VERSION 5.7 ;
  NOWIREEXTENSIONATPIN ON ;
  DIVIDERCHAR "/" ;
  BUSBITCHARS "[]" ;
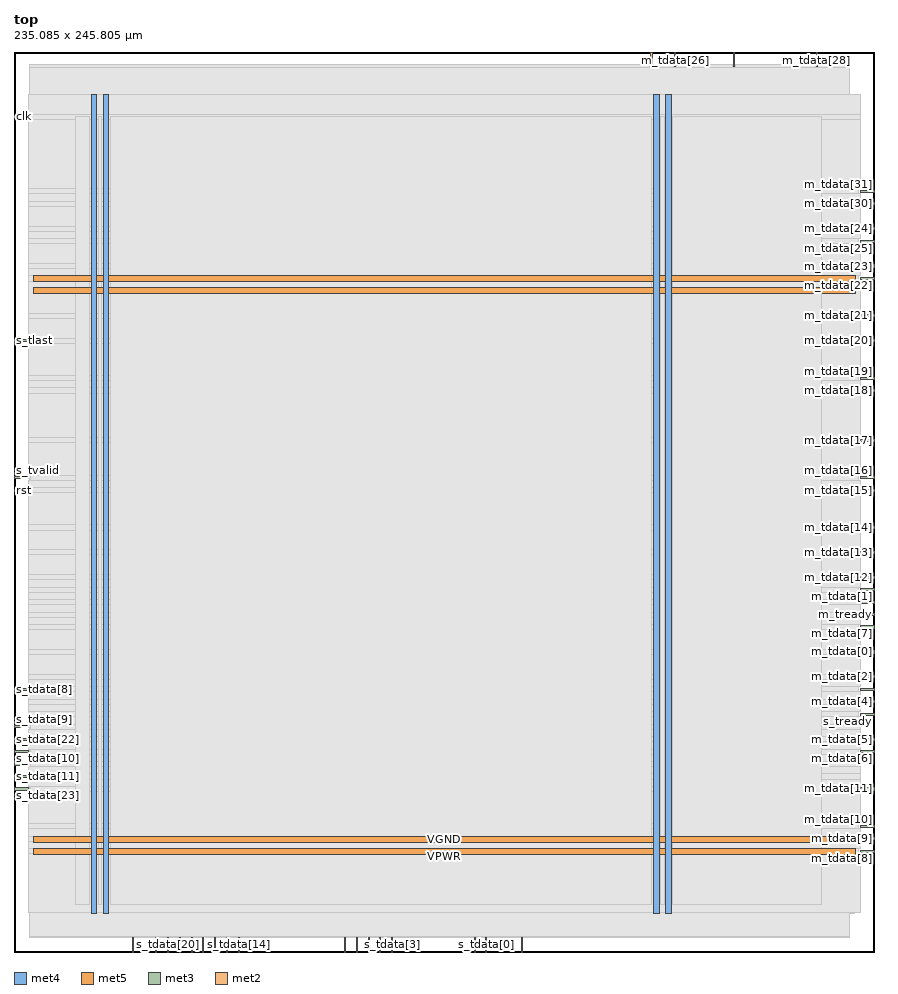
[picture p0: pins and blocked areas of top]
MACRO top
  CLASS BLOCK ;
  FOREIGN top ;
  ORIGIN 0.000 0.000 ;
  SIZE 235.085 BY 245.805 ;
  PIN VGND
    DIRECTION INOUT ;
    USE GROUND ;
    PORT
      LAYER met4 ;
        RECT 24.340 10.640 25.940 234.160 ;
    END
    PORT
      LAYER met4 ;
        RECT 177.940 10.640 179.540 234.160 ;
    END
    PORT
      LAYER met5 ;
        RECT 5.280 30.030 229.780 31.630 ;
    END
    PORT
      LAYER met5 ;
        RECT 5.280 183.210 229.780 184.810 ;
    END
  END VGND
  PIN VPWR
    DIRECTION INOUT ;
    USE POWER ;
    PORT
      LAYER met4 ;
        RECT 21.040 10.640 22.640 234.160 ;
    END
    PORT
      LAYER met4 ;
        RECT 174.640 10.640 176.240 234.160 ;
    END
    PORT
      LAYER met5 ;
        RECT 5.280 26.730 229.780 28.330 ;
    END
    PORT
      LAYER met5 ;
        RECT 5.280 179.910 229.780 181.510 ;
    END
  END VPWR
  PIN clk
    DIRECTION INPUT ;
    USE SIGNAL ;
    ANTENNAGATEAREA 0.852000 ;
    PORT
      LAYER met3 ;
        RECT 0.000 227.840 4.000 228.440 ;
    END
  END clk
  PIN m_tdata[0]
    DIRECTION OUTPUT ;
    USE SIGNAL ;
    ANTENNADIFFAREA 0.445500 ;
    PORT
      LAYER met3 ;
        RECT 231.085 81.640 235.085 82.240 ;
    END
  END m_tdata[0]
  PIN m_tdata[10]
    DIRECTION OUTPUT ;
    USE SIGNAL ;
    ANTENNADIFFAREA 0.445500 ;
    PORT
      LAYER met3 ;
        RECT 231.085 34.040 235.085 34.640 ;
    END
  END m_tdata[10]
  PIN m_tdata[11]
    DIRECTION OUTPUT ;
    USE SIGNAL ;
    ANTENNADIFFAREA 0.445500 ;
    PORT
      LAYER met3 ;
        RECT 231.085 44.240 235.085 44.840 ;
    END
  END m_tdata[11]
  PIN m_tdata[12]
    DIRECTION OUTPUT ;
    USE SIGNAL ;
    ANTENNADIFFAREA 0.445500 ;
    PORT
      LAYER met3 ;
        RECT 231.085 102.040 235.085 102.640 ;
    END
  END m_tdata[12]
  PIN m_tdata[13]
    DIRECTION OUTPUT ;
    USE SIGNAL ;
    ANTENNADIFFAREA 0.445500 ;
    PORT
      LAYER met3 ;
        RECT 231.085 108.840 235.085 109.440 ;
    END
  END m_tdata[13]
  PIN m_tdata[14]
    DIRECTION OUTPUT ;
    USE SIGNAL ;
    ANTENNADIFFAREA 0.445500 ;
    PORT
      LAYER met3 ;
        RECT 231.085 115.640 235.085 116.240 ;
    END
  END m_tdata[14]
  PIN m_tdata[15]
    DIRECTION OUTPUT ;
    USE SIGNAL ;
    ANTENNADIFFAREA 0.445500 ;
    PORT
      LAYER met3 ;
        RECT 231.085 125.840 235.085 126.440 ;
    END
  END m_tdata[15]
  PIN m_tdata[16]
    DIRECTION OUTPUT ;
    USE SIGNAL ;
    ANTENNADIFFAREA 0.445500 ;
    PORT
      LAYER met3 ;
        RECT 231.085 129.240 235.085 129.840 ;
    END
  END m_tdata[16]
  PIN m_tdata[17]
    DIRECTION OUTPUT ;
    USE SIGNAL ;
    ANTENNADIFFAREA 0.445500 ;
    PORT
      LAYER met3 ;
        RECT 231.085 139.440 235.085 140.040 ;
    END
  END m_tdata[17]
  PIN m_tdata[18]
    DIRECTION OUTPUT ;
    USE SIGNAL ;
    ANTENNADIFFAREA 0.445500 ;
    PORT
      LAYER met3 ;
        RECT 231.085 153.040 235.085 153.640 ;
    END
  END m_tdata[18]
  PIN m_tdata[19]
    DIRECTION OUTPUT ;
    USE SIGNAL ;
    ANTENNADIFFAREA 0.445500 ;
    PORT
      LAYER met3 ;
        RECT 231.085 156.440 235.085 157.040 ;
    END
  END m_tdata[19]
  PIN m_tdata[1]
    DIRECTION OUTPUT ;
    USE SIGNAL ;
    ANTENNADIFFAREA 0.445500 ;
    PORT
      LAYER met3 ;
        RECT 231.085 98.640 235.085 99.240 ;
    END
  END m_tdata[1]
  PIN m_tdata[20]
    DIRECTION OUTPUT ;
    USE SIGNAL ;
    ANTENNADIFFAREA 0.445500 ;
    PORT
      LAYER met3 ;
        RECT 231.085 166.640 235.085 167.240 ;
    END
  END m_tdata[20]
  PIN m_tdata[21]
    DIRECTION OUTPUT ;
    USE SIGNAL ;
    ANTENNADIFFAREA 0.445500 ;
    PORT
      LAYER met3 ;
        RECT 231.085 173.440 235.085 174.040 ;
    END
  END m_tdata[21]
  PIN m_tdata[22]
    DIRECTION OUTPUT ;
    USE SIGNAL ;
    ANTENNADIFFAREA 0.445500 ;
    PORT
      LAYER met3 ;
        RECT 231.085 183.640 235.085 184.240 ;
    END
  END m_tdata[22]
  PIN m_tdata[23]
    DIRECTION OUTPUT ;
    USE SIGNAL ;
    ANTENNADIFFAREA 0.445500 ;
    PORT
      LAYER met3 ;
        RECT 231.085 187.040 235.085 187.640 ;
    END
  END m_tdata[23]
  PIN m_tdata[24]
    DIRECTION OUTPUT ;
    USE SIGNAL ;
    ANTENNADIFFAREA 0.445500 ;
    PORT
      LAYER met3 ;
        RECT 231.085 197.240 235.085 197.840 ;
    END
  END m_tdata[24]
  PIN m_tdata[25]
    DIRECTION OUTPUT ;
    USE SIGNAL ;
    ANTENNADIFFAREA 0.445500 ;
    PORT
      LAYER met3 ;
        RECT 231.085 193.840 235.085 194.440 ;
    END
  END m_tdata[25]
  PIN m_tdata[26]
    DIRECTION OUTPUT ;
    USE SIGNAL ;
    ANTENNADIFFAREA 0.795200 ;
    PORT
      LAYER met2 ;
        RECT 180.410 241.805 180.690 245.805 ;
    END
  END m_tdata[26]
  PIN m_tdata[27]
    DIRECTION OUTPUT ;
    USE SIGNAL ;
    ANTENNADIFFAREA 0.795200 ;
    PORT
      LAYER met2 ;
        RECT 173.970 241.805 174.250 245.805 ;
    END
  END m_tdata[27]
  PIN m_tdata[28]
    DIRECTION OUTPUT ;
    USE SIGNAL ;
    ANTENNADIFFAREA 0.795200 ;
    PORT
      LAYER met2 ;
        RECT 219.050 241.805 219.330 245.805 ;
    END
  END m_tdata[28]
  PIN m_tdata[29]
    DIRECTION OUTPUT ;
    USE SIGNAL ;
    ANTENNADIFFAREA 0.795200 ;
    PORT
      LAYER met2 ;
        RECT 196.510 241.805 196.790 245.805 ;
    END
  END m_tdata[29]
  PIN m_tdata[2]
    DIRECTION OUTPUT ;
    USE SIGNAL ;
    ANTENNADIFFAREA 0.445500 ;
    PORT
      LAYER met3 ;
        RECT 231.085 74.840 235.085 75.440 ;
    END
  END m_tdata[2]
  PIN m_tdata[30]
    DIRECTION OUTPUT ;
    USE SIGNAL ;
    ANTENNADIFFAREA 0.445500 ;
    PORT
      LAYER met3 ;
        RECT 231.085 204.040 235.085 204.640 ;
    END
  END m_tdata[30]
  PIN m_tdata[31]
    DIRECTION OUTPUT ;
    USE SIGNAL ;
    ANTENNADIFFAREA 0.445500 ;
    PORT
      LAYER met3 ;
        RECT 231.085 207.440 235.085 208.040 ;
    END
  END m_tdata[31]
  PIN m_tdata[3]
    DIRECTION OUTPUT ;
    USE SIGNAL ;
    ANTENNADIFFAREA 0.445500 ;
    PORT
      LAYER met3 ;
        RECT 231.085 71.440 235.085 72.040 ;
    END
  END m_tdata[3]
  PIN m_tdata[4]
    DIRECTION OUTPUT ;
    USE SIGNAL ;
    ANTENNADIFFAREA 0.445500 ;
    PORT
      LAYER met3 ;
        RECT 231.085 68.040 235.085 68.640 ;
    END
  END m_tdata[4]
  PIN m_tdata[5]
    DIRECTION OUTPUT ;
    USE SIGNAL ;
    ANTENNADIFFAREA 0.445500 ;
    PORT
      LAYER met3 ;
        RECT 231.085 57.840 235.085 58.440 ;
    END
  END m_tdata[5]
  PIN m_tdata[6]
    DIRECTION OUTPUT ;
    USE SIGNAL ;
    ANTENNADIFFAREA 0.445500 ;
    PORT
      LAYER met3 ;
        RECT 231.085 54.440 235.085 55.040 ;
    END
  END m_tdata[6]
  PIN m_tdata[7]
    DIRECTION OUTPUT ;
    USE SIGNAL ;
    ANTENNADIFFAREA 0.445500 ;
    PORT
      LAYER met3 ;
        RECT 231.085 88.440 235.085 89.040 ;
    END
  END m_tdata[7]
  PIN m_tdata[8]
    DIRECTION OUTPUT ;
    USE SIGNAL ;
    ANTENNADIFFAREA 0.445500 ;
    PORT
      LAYER met3 ;
        RECT 231.085 27.240 235.085 27.840 ;
    END
  END m_tdata[8]
  PIN m_tdata[9]
    DIRECTION OUTPUT ;
    USE SIGNAL ;
    ANTENNADIFFAREA 0.445500 ;
    PORT
      LAYER met3 ;
        RECT 231.085 30.640 235.085 31.240 ;
    END
  END m_tdata[9]
  PIN m_tready
    DIRECTION INPUT ;
    USE SIGNAL ;
    ANTENNAGATEAREA 0.196500 ;
    PORT
      LAYER met3 ;
        RECT 231.085 91.840 235.085 92.440 ;
    END
  END m_tready
  PIN m_tvalid
    DIRECTION OUTPUT ;
    USE SIGNAL ;
    ANTENNADIFFAREA 0.445500 ;
    PORT
      LAYER met3 ;
        RECT 231.085 95.240 235.085 95.840 ;
    END
  END m_tvalid
  PIN rst
    DIRECTION INPUT ;
    USE SIGNAL ;
    ANTENNAGATEAREA 0.213000 ;
    PORT
      LAYER met3 ;
        RECT 0.000 125.840 4.000 126.440 ;
    END
  END rst
  PIN s_tdata[0]
    DIRECTION INPUT ;
    USE SIGNAL ;
    ANTENNAGATEAREA 0.196500 ;
    PORT
      LAYER met2 ;
        RECT 128.890 0.000 129.170 4.000 ;
    END
  END s_tdata[0]
  PIN s_tdata[10]
    DIRECTION INPUT ;
    USE SIGNAL ;
    ANTENNAGATEAREA 0.196500 ;
    PORT
      LAYER met3 ;
        RECT 0.000 54.440 4.000 55.040 ;
    END
  END s_tdata[10]
  PIN s_tdata[11]
    DIRECTION INPUT ;
    USE SIGNAL ;
    ANTENNAGATEAREA 0.126000 ;
    PORT
      LAYER met3 ;
        RECT 0.000 47.640 4.000 48.240 ;
    END
  END s_tdata[11]
  PIN s_tdata[12]
    DIRECTION INPUT ;
    USE SIGNAL ;
    ANTENNAGATEAREA 0.126000 ;
    PORT
      LAYER met2 ;
        RECT 38.730 0.000 39.010 4.000 ;
    END
  END s_tdata[12]
  PIN s_tdata[13]
    DIRECTION INPUT ;
    USE SIGNAL ;
    ANTENNAGATEAREA 0.213000 ;
    PORT
      LAYER met2 ;
        RECT 32.290 0.000 32.570 4.000 ;
    END
  END s_tdata[13]
  PIN s_tdata[14]
    DIRECTION INPUT ;
    USE SIGNAL ;
    ANTENNAGATEAREA 0.196500 ;
    PORT
      LAYER met2 ;
        RECT 61.270 0.000 61.550 4.000 ;
    END
  END s_tdata[14]
  PIN s_tdata[15]
    DIRECTION INPUT ;
    USE SIGNAL ;
    ANTENNAGATEAREA 0.196500 ;
    PORT
      LAYER met2 ;
        RECT 51.610 0.000 51.890 4.000 ;
    END
  END s_tdata[15]
  PIN s_tdata[16]
    DIRECTION INPUT ;
    USE SIGNAL ;
    ANTENNAGATEAREA 0.126000 ;
    PORT
      LAYER met2 ;
        RECT 58.050 0.000 58.330 4.000 ;
    END
  END s_tdata[16]
  PIN s_tdata[17]
    DIRECTION INPUT ;
    USE SIGNAL ;
    ANTENNAGATEAREA 0.196500 ;
    PORT
      LAYER met2 ;
        RECT 54.830 0.000 55.110 4.000 ;
    END
  END s_tdata[17]
  PIN s_tdata[18]
    DIRECTION INPUT ;
    USE SIGNAL ;
    ANTENNAGATEAREA 0.196500 ;
    PORT
      LAYER met2 ;
        RECT 48.390 0.000 48.670 4.000 ;
    END
  END s_tdata[18]
  PIN s_tdata[19]
    DIRECTION INPUT ;
    USE SIGNAL ;
    ANTENNAGATEAREA 0.126000 ;
    PORT
      LAYER met2 ;
        RECT 45.170 0.000 45.450 4.000 ;
    END
  END s_tdata[19]
  PIN s_tdata[1]
    DIRECTION INPUT ;
    USE SIGNAL ;
    ANTENNAGATEAREA 0.196500 ;
    PORT
      LAYER met2 ;
        RECT 138.550 0.000 138.830 4.000 ;
    END
  END s_tdata[1]
  PIN s_tdata[20]
    DIRECTION INPUT ;
    USE SIGNAL ;
    ANTENNAGATEAREA 0.196500 ;
    PORT
      LAYER met2 ;
        RECT 41.950 0.000 42.230 4.000 ;
    END
  END s_tdata[20]
  PIN s_tdata[21]
    DIRECTION INPUT ;
    USE SIGNAL ;
    ANTENNAGATEAREA 0.196500 ;
    PORT
      LAYER met3 ;
        RECT 0.000 51.040 4.000 51.640 ;
    END
  END s_tdata[21]
  PIN s_tdata[22]
    DIRECTION INPUT ;
    USE SIGNAL ;
    ANTENNAGATEAREA 0.213000 ;
    PORT
      LAYER met3 ;
        RECT 0.000 57.840 4.000 58.440 ;
    END
  END s_tdata[22]
  PIN s_tdata[23]
    DIRECTION INPUT ;
    USE SIGNAL ;
    ANTENNAGATEAREA 0.196500 ;
    PORT
      LAYER met3 ;
        RECT 0.000 44.240 4.000 44.840 ;
    END
  END s_tdata[23]
  PIN s_tdata[2]
    DIRECTION INPUT ;
    USE SIGNAL ;
    ANTENNAGATEAREA 0.196500 ;
    PORT
      LAYER met2 ;
        RECT 125.670 0.000 125.950 4.000 ;
    END
  END s_tdata[2]
  PIN s_tdata[3]
    DIRECTION INPUT ;
    USE SIGNAL ;
    ANTENNAGATEAREA 0.196500 ;
    PORT
      LAYER met2 ;
        RECT 103.130 0.000 103.410 4.000 ;
    END
  END s_tdata[3]
  PIN s_tdata[4]
    DIRECTION INPUT ;
    USE SIGNAL ;
    ANTENNAGATEAREA 0.196500 ;
    PORT
      LAYER met2 ;
        RECT 90.250 0.000 90.530 4.000 ;
    END
  END s_tdata[4]
  PIN s_tdata[5]
    DIRECTION INPUT ;
    USE SIGNAL ;
    ANTENNAGATEAREA 0.196500 ;
    PORT
      LAYER met2 ;
        RECT 93.470 0.000 93.750 4.000 ;
    END
  END s_tdata[5]
  PIN s_tdata[6]
    DIRECTION INPUT ;
    USE SIGNAL ;
    ANTENNAGATEAREA 0.196500 ;
    PORT
      LAYER met2 ;
        RECT 99.910 0.000 100.190 4.000 ;
    END
  END s_tdata[6]
  PIN s_tdata[7]
    DIRECTION INPUT ;
    USE SIGNAL ;
    ANTENNAGATEAREA 0.196500 ;
    PORT
      LAYER met2 ;
        RECT 96.690 0.000 96.970 4.000 ;
    END
  END s_tdata[7]
  PIN s_tdata[8]
    DIRECTION INPUT ;
    USE SIGNAL ;
    ANTENNAGATEAREA 0.159000 ;
    PORT
      LAYER met3 ;
        RECT 0.000 71.440 4.000 72.040 ;
    END
  END s_tdata[8]
  PIN s_tdata[9]
    DIRECTION INPUT ;
    USE SIGNAL ;
    ANTENNAGATEAREA 0.196500 ;
    PORT
      LAYER met3 ;
        RECT 0.000 61.240 4.000 61.840 ;
    END
  END s_tdata[9]
  PIN s_tlast
    DIRECTION INPUT ;
    USE SIGNAL ;
    ANTENNAGATEAREA 0.196500 ;
    PORT
      LAYER met3 ;
        RECT 0.000 166.640 4.000 167.240 ;
    END
  END s_tlast
  PIN s_tready
    DIRECTION OUTPUT ;
    USE SIGNAL ;
    ANTENNADIFFAREA 0.445500 ;
    PORT
      LAYER met3 ;
        RECT 231.085 64.640 235.085 65.240 ;
    END
  END s_tready
  PIN s_tvalid
    DIRECTION INPUT ;
    USE SIGNAL ;
    ANTENNAGATEAREA 0.196500 ;
    PORT
      LAYER met3 ;
        RECT 0.000 129.240 4.000 129.840 ;
    END
  END s_tvalid
  OBS
      LAYER nwell ;
        RECT 5.330 10.795 229.730 234.005 ;
      LAYER li1 ;
        RECT 5.520 10.795 229.540 234.005 ;
      LAYER met1 ;
        RECT 4.210 10.640 229.540 234.160 ;
      LAYER met2 ;
        RECT 4.230 241.525 173.690 242.490 ;
        RECT 174.530 241.525 180.130 242.490 ;
        RECT 180.970 241.525 196.230 242.490 ;
        RECT 197.070 241.525 218.770 242.490 ;
        RECT 219.610 241.525 228.070 242.490 ;
        RECT 4.230 4.280 228.070 241.525 ;
        RECT 4.230 4.000 32.010 4.280 ;
        RECT 32.850 4.000 38.450 4.280 ;
        RECT 39.290 4.000 41.670 4.280 ;
        RECT 42.510 4.000 44.890 4.280 ;
        RECT 45.730 4.000 48.110 4.280 ;
        RECT 48.950 4.000 51.330 4.280 ;
        RECT 52.170 4.000 54.550 4.280 ;
        RECT 55.390 4.000 57.770 4.280 ;
        RECT 58.610 4.000 60.990 4.280 ;
        RECT 61.830 4.000 89.970 4.280 ;
        RECT 90.810 4.000 93.190 4.280 ;
        RECT 94.030 4.000 96.410 4.280 ;
        RECT 97.250 4.000 99.630 4.280 ;
        RECT 100.470 4.000 102.850 4.280 ;
        RECT 103.690 4.000 125.390 4.280 ;
        RECT 126.230 4.000 128.610 4.280 ;
        RECT 129.450 4.000 138.270 4.280 ;
        RECT 139.110 4.000 228.070 4.280 ;
      LAYER met3 ;
        RECT 3.990 228.840 231.085 234.085 ;
        RECT 4.400 227.440 231.085 228.840 ;
        RECT 3.990 208.440 231.085 227.440 ;
        RECT 3.990 207.040 230.685 208.440 ;
        RECT 3.990 205.040 231.085 207.040 ;
        RECT 3.990 203.640 230.685 205.040 ;
        RECT 3.990 198.240 231.085 203.640 ;
        RECT 3.990 196.840 230.685 198.240 ;
        RECT 3.990 194.840 231.085 196.840 ;
        RECT 3.990 193.440 230.685 194.840 ;
        RECT 3.990 188.040 231.085 193.440 ;
        RECT 3.990 186.640 230.685 188.040 ;
        RECT 3.990 184.640 231.085 186.640 ;
        RECT 3.990 183.240 230.685 184.640 ;
        RECT 3.990 174.440 231.085 183.240 ;
        RECT 3.990 173.040 230.685 174.440 ;
        RECT 3.990 167.640 231.085 173.040 ;
        RECT 4.400 166.240 230.685 167.640 ;
        RECT 3.990 157.440 231.085 166.240 ;
        RECT 3.990 156.040 230.685 157.440 ;
        RECT 3.990 154.040 231.085 156.040 ;
        RECT 3.990 152.640 230.685 154.040 ;
        RECT 3.990 140.440 231.085 152.640 ;
        RECT 3.990 139.040 230.685 140.440 ;
        RECT 3.990 130.240 231.085 139.040 ;
        RECT 4.400 128.840 230.685 130.240 ;
        RECT 3.990 126.840 231.085 128.840 ;
        RECT 4.400 125.440 230.685 126.840 ;
        RECT 3.990 116.640 231.085 125.440 ;
        RECT 3.990 115.240 230.685 116.640 ;
        RECT 3.990 109.840 231.085 115.240 ;
        RECT 3.990 108.440 230.685 109.840 ;
        RECT 3.990 103.040 231.085 108.440 ;
        RECT 3.990 101.640 230.685 103.040 ;
        RECT 3.990 99.640 231.085 101.640 ;
        RECT 3.990 98.240 230.685 99.640 ;
        RECT 3.990 96.240 231.085 98.240 ;
        RECT 3.990 94.840 230.685 96.240 ;
        RECT 3.990 92.840 231.085 94.840 ;
        RECT 3.990 91.440 230.685 92.840 ;
        RECT 3.990 89.440 231.085 91.440 ;
        RECT 3.990 88.040 230.685 89.440 ;
        RECT 3.990 82.640 231.085 88.040 ;
        RECT 3.990 81.240 230.685 82.640 ;
        RECT 3.990 75.840 231.085 81.240 ;
        RECT 3.990 74.440 230.685 75.840 ;
        RECT 3.990 72.440 231.085 74.440 ;
        RECT 4.400 71.040 230.685 72.440 ;
        RECT 3.990 69.040 231.085 71.040 ;
        RECT 3.990 67.640 230.685 69.040 ;
        RECT 3.990 65.640 231.085 67.640 ;
        RECT 3.990 64.240 230.685 65.640 ;
        RECT 3.990 62.240 231.085 64.240 ;
        RECT 4.400 60.840 231.085 62.240 ;
        RECT 3.990 58.840 231.085 60.840 ;
        RECT 4.400 57.440 230.685 58.840 ;
        RECT 3.990 55.440 231.085 57.440 ;
        RECT 4.400 54.040 230.685 55.440 ;
        RECT 3.990 52.040 231.085 54.040 ;
        RECT 4.400 50.640 231.085 52.040 ;
        RECT 3.990 48.640 231.085 50.640 ;
        RECT 4.400 47.240 231.085 48.640 ;
        RECT 3.990 45.240 231.085 47.240 ;
        RECT 4.400 43.840 230.685 45.240 ;
        RECT 3.990 35.040 231.085 43.840 ;
        RECT 3.990 33.640 230.685 35.040 ;
        RECT 3.990 31.640 231.085 33.640 ;
        RECT 3.990 30.240 230.685 31.640 ;
        RECT 3.990 28.240 231.085 30.240 ;
        RECT 3.990 26.840 230.685 28.240 ;
        RECT 3.990 10.715 231.085 26.840 ;
      LAYER met4 ;
        RECT 16.855 13.095 20.640 228.305 ;
        RECT 23.040 13.095 23.940 228.305 ;
        RECT 26.340 13.095 174.240 228.305 ;
        RECT 176.640 13.095 177.540 228.305 ;
        RECT 179.940 13.095 220.505 228.305 ;
  END
END top
END LIBRARY

